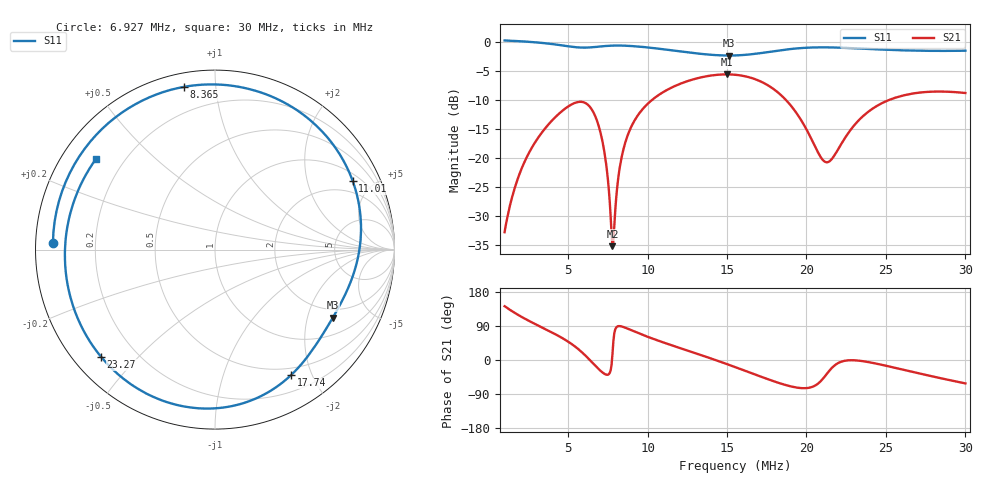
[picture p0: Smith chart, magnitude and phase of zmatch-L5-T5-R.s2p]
# HZ S RI R 50
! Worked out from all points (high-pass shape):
!   505 points, 1 MHz to 30 MHz, reference 50 ohm
!   highest |S21| = -5.66 dB at 14.98 MHz (marker M1); lowest = -35.3 dB at 7.79 MHz (marker M2)
!   |S21| within 3 dB of the highest: 11.01 MHz to 18.15 MHz (7.139 MHz wide, 49 % of centre); 27.73 MHz to 29.03 MHz (1.298 MHz wide, 4.58 % of centre)
!   lowest |S11| = -2.4 dB at 15.1 MHz (marker M3), VSWR 7.26, Z = 81.1 - j145 ohm
!   |S11| at or under -10 dB: nowhere
!   S12 and S22 are empty: the file has one direction only
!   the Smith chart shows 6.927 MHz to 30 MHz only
!   S11 on the Smith chart (normalised r, x): 6.927 MHz: 0.05, +0.02; 8.365 MHz: 0.07, +0.82; 11.01 MHz: 1.33, +3.82; 17.74 MHz: 0.40, -1.70; 23.27 MHz: 0.08, -0.39; 30 MHz: 0.10, +0.33
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1000000  -0.6385 0.7976  -0.0179 0.0141  0 0  0 0
2438500  0.3212 0.9436  -0.0273 0.1  0 0  0 0
3934540  0.9434 0.1381  0.0579 0.197  0 0  0 0
4855180  0.7078 -0.5814  0.1638 0.2112  0 0  0 0
5833360  -0.2103 -0.8619  0.281 0.1116  0 0  0 0
6408760  -0.7374 -0.4991  0.2692 -0.00951  0 0  0 0
6926620  -0.9031 0.0364  0.1698 -0.0768  0 0  0 0
7386940  -0.7845 0.4728  0.0695 -0.0552  0 0  0 0
7789720  -0.5561 0.7358  0.0165 0.00494  0 0  0 0
8365120  -0.1743 0.9064  0.00251 0.1008  0 0  0 0
9458380  0.407 0.8075  0.081 0.2248  0 0  0 0
1.066672e7  0.7245 0.479  0.2161 0.2677  0 0  0 0
1.101196e7  0.7673 0.382  0.2561 0.2654  0 0  0 0
1.498222e7  0.664 -0.3657  0.5122 -0.0964  0 0  0 0
1.50973e7  0.6561 -0.3795  0.5088 -0.1119  0 0  0 0
1.550008e7  0.6279 -0.4267  0.4904 -0.1646  0 0  0 0
1.774414e7  0.4235 -0.6992  0.2426 -0.325  0 0  0 0
2.033344e7  -0.0725 -0.8852  0.0455 -0.1348  0 0  0 0
2.136916e7  -0.3028 -0.8376  0.078 -0.0483  0 0  0 0
2.326798e7  -0.6346 -0.5976  0.2084 -0.00589  0 0  0 0
2.51668e7  -0.8055 -0.2655  0.2993 -0.09  0 0  0 0
3.000016e7  -0.6633 0.5048  0.1704 -0.3173  0 0  0 0
